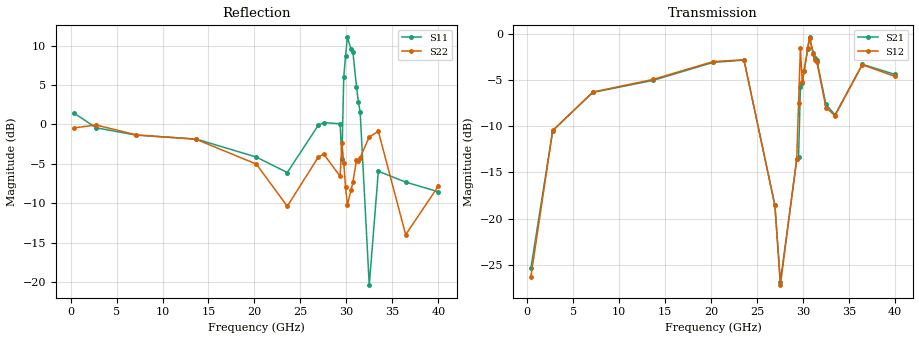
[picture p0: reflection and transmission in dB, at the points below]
! Network Analyzer HP8722ES.07.66: Jul 25, 2000 Serial No. US39175408
! 26 Oct 2004  08:37:50
! Frequency  S11  S21  S12  S22
# HZ  S  DB R  50
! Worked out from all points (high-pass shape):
!   201 points, 400 MHz to 40 GHz, reference 50 ohm
!   highest |S21| = -0.42 dB at 30.69 GHz (marker M1); lowest = -26.8 dB at 27.53 GHz (marker M2)
!   |S21| within 3 dB of the highest: 18.65 GHz to 24.09 GHz (5.444 GHz wide, 25.5 % of centre); 34.54 GHz to 36.47 GHz (1.931 GHz wide, 5.44 % of centre) (the widest 2 of 3)
!   lowest |S11| = -20.4 dB at 32.48 GHz (marker M3), VSWR 1.21, Z = 42 - j3.76 ohm
!   |S11| at or under -10 dB: 32.2 GHz to 33.02 GHz (827 MHz wide, 2.54 % of centre); 38.1 GHz to 38.59 GHz (490.1 MHz wide, 1.28 % of centre)
!   |S22| runs from -14.0 to 0.7 dB; largest |S21 - S12| = 0.33
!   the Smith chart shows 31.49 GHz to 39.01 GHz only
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4e8  1.41 -1.1  -25.37 88.8  -26.30 92.6  -0.45 3.9
2.776e9  -0.43 -31.0  -10.50 55.6  -10.48 54.6  -0.08 -37.4
7.132e9  -1.37 -60.1  -6.37 20.6  -6.33 19.1  -1.33 -80.7
1.3666e10  -1.86 -66.9  -5.07 -5.0  -4.97 -5.0  -1.90 -122.5
2.02e10  -4.15 -66.2  -3.13 -33.4  -3.04 -33.0  -5.04 -175.7
2.3566e10  -6.11 -29.7  -2.87 -70.5  -2.84 -71.1  -10.39 79.6
2.6932e10  -0.12 -43.7  -18.59 -113.9  -18.59 -114.2  -4.16 -43.0
2.7526e10  0.22 -46.9  -26.84 -49.4  -27.20 -49.3  -3.77 -57.4
2.9308e10  0.07 -22.8  -13.58 22.2  -13.53 21.5  -6.58 -66.7
2.9506e10  -4.38 29.8  -13.31 -11.4  -7.46 1.3  -2.41 98.2
2.9704e10  5.95 -67.2  -5.79 -19.8  -1.55 -14.4  -4.86 -163.2
2.9902e10  8.66 -47.5  -5.31 13.2  -5.24 13.5  -7.93 -104.3
3.01e10  11.03 -61.3  -4.07 6.7  -4.10 6.7  -10.22 -100.5
3.0496e10  9.54 -75.7  -1.69 -7.4  -1.60 -7.6  -8.32 -102.5
3.0694e10  9.21 82.8  -0.42 -21.3  -0.46 -20.6  -7.34 87.7
3.109e10  4.78 43.7  -2.07 -48.0  -2.18 -47.7  -4.51 87.7
3.1288e10  2.89 40.4  -2.67 -49.1  -2.88 -49.4  -4.63 86.0
3.1486e10  1.58 -139.2  -2.86 -53.5  -3.03 -54.8  -4.22 -99.7
3.2476e10  -20.39 -152.3  -7.66 -72.3  -8.00 -71.8  -1.60 -127.5
3.3466e10  -5.95 -20.1  -8.79 -9.9  -8.89 -10.7  -0.89 -150.8
3.6436e10  -7.32 -65.2  -3.33 -62.8  -3.38 -63.9  -13.99 -138.6
4e10  -8.56 -66.8  -4.43 -59.3  -4.64 -58.6  -7.82 -141.7
